VERSION 5.7 ;
BUSBITCHARS "[]" ;
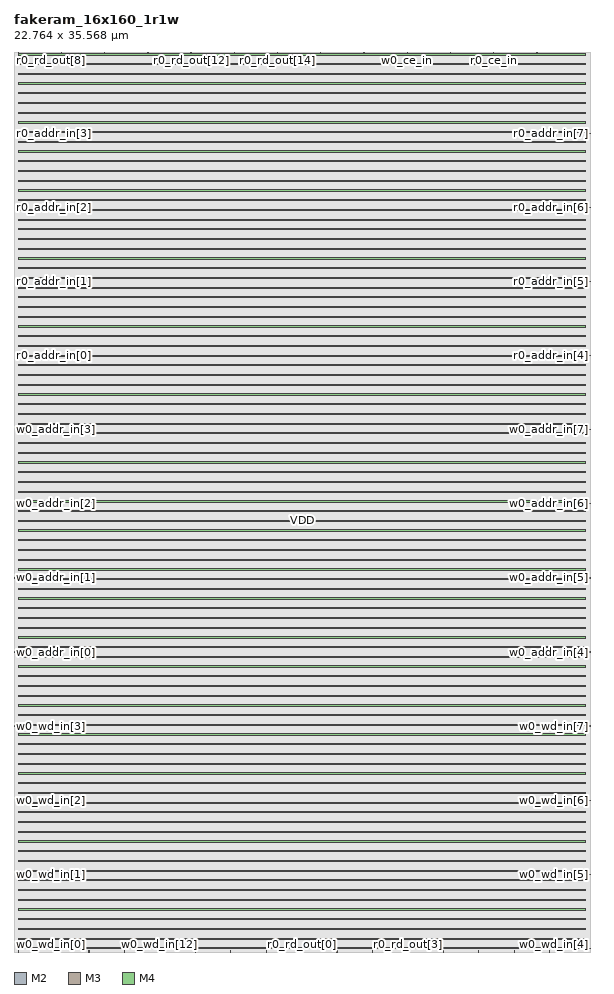
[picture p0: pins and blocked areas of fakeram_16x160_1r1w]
MACRO fakeram_16x160_1r1w
  FOREIGN fakeram_16x160_1r1w 0 0 ;
  SYMMETRY X Y R90 ;
  SIZE 22.764 BY 35.568 ;
  CLASS BLOCK ;
  PIN w0_wd_in[0]
    DIRECTION INPUT ;
    USE SIGNAL ;
    SHAPE ABUTMENT ;
    PORT
      LAYER M2 ;
      RECT 0.000 0.138 0.036 0.150 ;
    END
  END w0_wd_in[0]
  PIN w0_wd_in[1]
    DIRECTION INPUT ;
    USE SIGNAL ;
    SHAPE ABUTMENT ;
    PORT
      LAYER M2 ;
      RECT 0.000 3.066 0.036 3.078 ;
    END
  END w0_wd_in[1]
  PIN w0_wd_in[2]
    DIRECTION INPUT ;
    USE SIGNAL ;
    SHAPE ABUTMENT ;
    PORT
      LAYER M2 ;
      RECT 0.000 5.994 0.036 6.006 ;
    END
  END w0_wd_in[2]
  PIN w0_wd_in[3]
    DIRECTION INPUT ;
    USE SIGNAL ;
    SHAPE ABUTMENT ;
    PORT
      LAYER M2 ;
      RECT 0.000 8.922 0.036 8.934 ;
    END
  END w0_wd_in[3]
  PIN w0_wd_in[4]
    DIRECTION INPUT ;
    USE SIGNAL ;
    SHAPE ABUTMENT ;
    PORT
      LAYER M2 ;
      RECT 22.728 0.138 22.764 0.150 ;
    END
  END w0_wd_in[4]
  PIN w0_wd_in[5]
    DIRECTION INPUT ;
    USE SIGNAL ;
    SHAPE ABUTMENT ;
    PORT
      LAYER M2 ;
      RECT 22.728 3.066 22.764 3.078 ;
    END
  END w0_wd_in[5]
  PIN w0_wd_in[6]
    DIRECTION INPUT ;
    USE SIGNAL ;
    SHAPE ABUTMENT ;
    PORT
      LAYER M2 ;
      RECT 22.728 5.994 22.764 6.006 ;
    END
  END w0_wd_in[6]
  PIN w0_wd_in[7]
    DIRECTION INPUT ;
    USE SIGNAL ;
    SHAPE ABUTMENT ;
    PORT
      LAYER M2 ;
      RECT 22.728 8.922 22.764 8.934 ;
    END
  END w0_wd_in[7]
  PIN w0_wd_in[8]
    DIRECTION INPUT ;
    USE SIGNAL ;
    SHAPE ABUTMENT ;
    PORT
      LAYER M3 ;
      RECT 0.161 0.000 0.175 0.042 ;
    END
  END w0_wd_in[8]
  PIN w0_wd_in[9]
    DIRECTION INPUT ;
    USE SIGNAL ;
    SHAPE ABUTMENT ;
    PORT
      LAYER M3 ;
      RECT 1.561 0.000 1.575 0.042 ;
    END
  END w0_wd_in[9]
  PIN w0_wd_in[10]
    DIRECTION INPUT ;
    USE SIGNAL ;
    SHAPE ABUTMENT ;
    PORT
      LAYER M3 ;
      RECT 2.961 0.000 2.975 0.042 ;
    END
  END w0_wd_in[10]
  PIN w0_wd_in[11]
    DIRECTION INPUT ;
    USE SIGNAL ;
    SHAPE ABUTMENT ;
    PORT
      LAYER M3 ;
      RECT 4.361 0.000 4.375 0.042 ;
    END
  END w0_wd_in[11]
  PIN w0_wd_in[12]
    DIRECTION INPUT ;
    USE SIGNAL ;
    SHAPE ABUTMENT ;
    PORT
      LAYER M3 ;
      RECT 5.761 0.000 5.775 0.042 ;
    END
  END w0_wd_in[12]
  PIN w0_wd_in[13]
    DIRECTION INPUT ;
    USE SIGNAL ;
    SHAPE ABUTMENT ;
    PORT
      LAYER M3 ;
      RECT 7.161 0.000 7.175 0.042 ;
    END
  END w0_wd_in[13]
  PIN w0_wd_in[14]
    DIRECTION INPUT ;
    USE SIGNAL ;
    SHAPE ABUTMENT ;
    PORT
      LAYER M3 ;
      RECT 8.561 0.000 8.575 0.042 ;
    END
  END w0_wd_in[14]
  PIN w0_wd_in[15]
    DIRECTION INPUT ;
    USE SIGNAL ;
    SHAPE ABUTMENT ;
    PORT
      LAYER M3 ;
      RECT 9.961 0.000 9.975 0.042 ;
    END
  END w0_wd_in[15]
  PIN r0_rd_out[0]
    DIRECTION OUTPUT ;
    USE SIGNAL ;
    SHAPE ABUTMENT ;
    PORT
      LAYER M3 ;
      RECT 11.361 0.000 11.375 0.042 ;
    END
  END r0_rd_out[0]
  PIN r0_rd_out[1]
    DIRECTION OUTPUT ;
    USE SIGNAL ;
    SHAPE ABUTMENT ;
    PORT
      LAYER M3 ;
      RECT 12.761 0.000 12.775 0.042 ;
    END
  END r0_rd_out[1]
  PIN r0_rd_out[2]
    DIRECTION OUTPUT ;
    USE SIGNAL ;
    SHAPE ABUTMENT ;
    PORT
      LAYER M3 ;
      RECT 14.161 0.000 14.175 0.042 ;
    END
  END r0_rd_out[2]
  PIN r0_rd_out[3]
    DIRECTION OUTPUT ;
    USE SIGNAL ;
    SHAPE ABUTMENT ;
    PORT
      LAYER M3 ;
      RECT 15.561 0.000 15.575 0.042 ;
    END
  END r0_rd_out[3]
  PIN r0_rd_out[4]
    DIRECTION OUTPUT ;
    USE SIGNAL ;
    SHAPE ABUTMENT ;
    PORT
      LAYER M3 ;
      RECT 16.961 0.000 16.975 0.042 ;
    END
  END r0_rd_out[4]
  PIN r0_rd_out[5]
    DIRECTION OUTPUT ;
    USE SIGNAL ;
    SHAPE ABUTMENT ;
    PORT
      LAYER M3 ;
      RECT 18.361 0.000 18.375 0.042 ;
    END
  END r0_rd_out[5]
  PIN r0_rd_out[6]
    DIRECTION OUTPUT ;
    USE SIGNAL ;
    SHAPE ABUTMENT ;
    PORT
      LAYER M3 ;
      RECT 19.761 0.000 19.775 0.042 ;
    END
  END r0_rd_out[6]
  PIN r0_rd_out[7]
    DIRECTION OUTPUT ;
    USE SIGNAL ;
    SHAPE ABUTMENT ;
    PORT
      LAYER M3 ;
      RECT 21.161 0.000 21.175 0.042 ;
    END
  END r0_rd_out[7]
  PIN r0_rd_out[8]
    DIRECTION OUTPUT ;
    USE SIGNAL ;
    SHAPE ABUTMENT ;
    PORT
      LAYER M3 ;
      RECT 0.161 35.526 0.175 35.568 ;
    END
  END r0_rd_out[8]
  PIN r0_rd_out[9]
    DIRECTION OUTPUT ;
    USE SIGNAL ;
    SHAPE ABUTMENT ;
    PORT
      LAYER M3 ;
      RECT 1.869 35.526 1.883 35.568 ;
    END
  END r0_rd_out[9]
  PIN r0_rd_out[10]
    DIRECTION OUTPUT ;
    USE SIGNAL ;
    SHAPE ABUTMENT ;
    PORT
      LAYER M3 ;
      RECT 3.577 35.526 3.591 35.568 ;
    END
  END r0_rd_out[10]
  PIN r0_rd_out[11]
    DIRECTION OUTPUT ;
    USE SIGNAL ;
    SHAPE ABUTMENT ;
    PORT
      LAYER M3 ;
      RECT 5.285 35.526 5.299 35.568 ;
    END
  END r0_rd_out[11]
  PIN r0_rd_out[12]
    DIRECTION OUTPUT ;
    USE SIGNAL ;
    SHAPE ABUTMENT ;
    PORT
      LAYER M3 ;
      RECT 6.993 35.526 7.007 35.568 ;
    END
  END r0_rd_out[12]
  PIN r0_rd_out[13]
    DIRECTION OUTPUT ;
    USE SIGNAL ;
    SHAPE ABUTMENT ;
    PORT
      LAYER M3 ;
      RECT 8.701 35.526 8.715 35.568 ;
    END
  END r0_rd_out[13]
  PIN r0_rd_out[14]
    DIRECTION OUTPUT ;
    USE SIGNAL ;
    SHAPE ABUTMENT ;
    PORT
      LAYER M3 ;
      RECT 10.409 35.526 10.423 35.568 ;
    END
  END r0_rd_out[14]
  PIN r0_rd_out[15]
    DIRECTION OUTPUT ;
    USE SIGNAL ;
    SHAPE ABUTMENT ;
    PORT
      LAYER M3 ;
      RECT 12.117 35.526 12.131 35.568 ;
    END
  END r0_rd_out[15]
  PIN w0_addr_in[0]
    DIRECTION INPUT ;
    USE SIGNAL ;
    SHAPE ABUTMENT ;
    PORT
      LAYER M2 ;
      RECT 0.000 11.850 0.036 11.862 ;
    END
  END w0_addr_in[0]
  PIN w0_addr_in[1]
    DIRECTION INPUT ;
    USE SIGNAL ;
    SHAPE ABUTMENT ;
    PORT
      LAYER M2 ;
      RECT 0.000 14.778 0.036 14.790 ;
    END
  END w0_addr_in[1]
  PIN w0_addr_in[2]
    DIRECTION INPUT ;
    USE SIGNAL ;
    SHAPE ABUTMENT ;
    PORT
      LAYER M2 ;
      RECT 0.000 17.706 0.036 17.718 ;
    END
  END w0_addr_in[2]
  PIN w0_addr_in[3]
    DIRECTION INPUT ;
    USE SIGNAL ;
    SHAPE ABUTMENT ;
    PORT
      LAYER M2 ;
      RECT 0.000 20.634 0.036 20.646 ;
    END
  END w0_addr_in[3]
  PIN w0_addr_in[4]
    DIRECTION INPUT ;
    USE SIGNAL ;
    SHAPE ABUTMENT ;
    PORT
      LAYER M2 ;
      RECT 22.728 11.850 22.764 11.862 ;
    END
  END w0_addr_in[4]
  PIN w0_addr_in[5]
    DIRECTION INPUT ;
    USE SIGNAL ;
    SHAPE ABUTMENT ;
    PORT
      LAYER M2 ;
      RECT 22.728 14.778 22.764 14.790 ;
    END
  END w0_addr_in[5]
  PIN w0_addr_in[6]
    DIRECTION INPUT ;
    USE SIGNAL ;
    SHAPE ABUTMENT ;
    PORT
      LAYER M2 ;
      RECT 22.728 17.706 22.764 17.718 ;
    END
  END w0_addr_in[6]
  PIN w0_addr_in[7]
    DIRECTION INPUT ;
    USE SIGNAL ;
    SHAPE ABUTMENT ;
    PORT
      LAYER M2 ;
      RECT 22.728 20.634 22.764 20.646 ;
    END
  END w0_addr_in[7]
  PIN r0_addr_in[0]
    DIRECTION INPUT ;
    USE SIGNAL ;
    SHAPE ABUTMENT ;
    PORT
      LAYER M2 ;
      RECT 0.000 23.562 0.036 23.574 ;
    END
  END r0_addr_in[0]
  PIN r0_addr_in[1]
    DIRECTION INPUT ;
    USE SIGNAL ;
    SHAPE ABUTMENT ;
    PORT
      LAYER M2 ;
      RECT 0.000 26.490 0.036 26.502 ;
    END
  END r0_addr_in[1]
  PIN r0_addr_in[2]
    DIRECTION INPUT ;
    USE SIGNAL ;
    SHAPE ABUTMENT ;
    PORT
      LAYER M2 ;
      RECT 0.000 29.418 0.036 29.430 ;
    END
  END r0_addr_in[2]
  PIN r0_addr_in[3]
    DIRECTION INPUT ;
    USE SIGNAL ;
    SHAPE ABUTMENT ;
    PORT
      LAYER M2 ;
      RECT 0.000 32.346 0.036 32.358 ;
    END
  END r0_addr_in[3]
  PIN r0_addr_in[4]
    DIRECTION INPUT ;
    USE SIGNAL ;
    SHAPE ABUTMENT ;
    PORT
      LAYER M2 ;
      RECT 22.728 23.562 22.764 23.574 ;
    END
  END r0_addr_in[4]
  PIN r0_addr_in[5]
    DIRECTION INPUT ;
    USE SIGNAL ;
    SHAPE ABUTMENT ;
    PORT
      LAYER M2 ;
      RECT 22.728 26.490 22.764 26.502 ;
    END
  END r0_addr_in[5]
  PIN r0_addr_in[6]
    DIRECTION INPUT ;
    USE SIGNAL ;
    SHAPE ABUTMENT ;
    PORT
      LAYER M2 ;
      RECT 22.728 29.418 22.764 29.430 ;
    END
  END r0_addr_in[6]
  PIN r0_addr_in[7]
    DIRECTION INPUT ;
    USE SIGNAL ;
    SHAPE ABUTMENT ;
    PORT
      LAYER M2 ;
      RECT 22.728 32.346 22.764 32.358 ;
    END
  END r0_addr_in[7]
  PIN w0_we_in
    DIRECTION INPUT ;
    USE SIGNAL ;
    SHAPE ABUTMENT ;
    PORT
      LAYER M3 ;
      RECT 13.825 35.526 13.839 35.568 ;
    END
  END w0_we_in
  PIN w0_ce_in
    DIRECTION INPUT ;
    USE SIGNAL ;
    SHAPE ABUTMENT ;
    PORT
      LAYER M3 ;
      RECT 15.533 35.526 15.547 35.568 ;
    END
  END w0_ce_in
  PIN w0_clk
    DIRECTION INPUT ;
    USE SIGNAL ;
    SHAPE ABUTMENT ;
    PORT
      LAYER M3 ;
      RECT 17.241 35.526 17.255 35.568 ;
    END
  END w0_clk
  PIN r0_ce_in
    DIRECTION INPUT ;
    USE SIGNAL ;
    SHAPE ABUTMENT ;
    PORT
      LAYER M3 ;
      RECT 18.949 35.526 18.963 35.568 ;
    END
  END r0_ce_in
  PIN r0_clk
    DIRECTION INPUT ;
    USE SIGNAL ;
    SHAPE ABUTMENT ;
    PORT
      LAYER M3 ;
      RECT 20.657 35.526 20.671 35.568 ;
    END
  END r0_clk
  PIN VSS
    DIRECTION INOUT ;
    USE GROUND ;
    PORT
      LAYER M4 ;
      RECT 0.168 0.120 22.596 0.168 ;
      RECT 0.168 0.504 22.596 0.552 ;
      RECT 0.168 0.888 22.596 0.936 ;
      RECT 0.168 1.272 22.596 1.320 ;
      RECT 0.168 1.656 22.596 1.704 ;
      RECT 0.168 2.040 22.596 2.088 ;
      RECT 0.168 2.424 22.596 2.472 ;
      RECT 0.168 2.808 22.596 2.856 ;
      RECT 0.168 3.192 22.596 3.240 ;
      RECT 0.168 3.576 22.596 3.624 ;
      RECT 0.168 3.960 22.596 4.008 ;
      RECT 0.168 4.344 22.596 4.392 ;
      RECT 0.168 4.728 22.596 4.776 ;
      RECT 0.168 5.112 22.596 5.160 ;
      RECT 0.168 5.496 22.596 5.544 ;
      RECT 0.168 5.880 22.596 5.928 ;
      RECT 0.168 6.264 22.596 6.312 ;
      RECT 0.168 6.648 22.596 6.696 ;
      RECT 0.168 7.032 22.596 7.080 ;
      RECT 0.168 7.416 22.596 7.464 ;
      RECT 0.168 7.800 22.596 7.848 ;
      RECT 0.168 8.184 22.596 8.232 ;
      RECT 0.168 8.568 22.596 8.616 ;
      RECT 0.168 8.952 22.596 9.000 ;
      RECT 0.168 9.336 22.596 9.384 ;
      RECT 0.168 9.720 22.596 9.768 ;
      RECT 0.168 10.104 22.596 10.152 ;
      RECT 0.168 10.488 22.596 10.536 ;
      RECT 0.168 10.872 22.596 10.920 ;
      RECT 0.168 11.256 22.596 11.304 ;
      RECT 0.168 11.640 22.596 11.688 ;
      RECT 0.168 12.024 22.596 12.072 ;
      RECT 0.168 12.408 22.596 12.456 ;
      RECT 0.168 12.792 22.596 12.840 ;
      RECT 0.168 13.176 22.596 13.224 ;
      RECT 0.168 13.560 22.596 13.608 ;
      RECT 0.168 13.944 22.596 13.992 ;
      RECT 0.168 14.328 22.596 14.376 ;
      RECT 0.168 14.712 22.596 14.760 ;
      RECT 0.168 15.096 22.596 15.144 ;
      RECT 0.168 15.480 22.596 15.528 ;
      RECT 0.168 15.864 22.596 15.912 ;
      RECT 0.168 16.248 22.596 16.296 ;
      RECT 0.168 16.632 22.596 16.680 ;
      RECT 0.168 17.016 22.596 17.064 ;
      RECT 0.168 17.400 22.596 17.448 ;
      RECT 0.168 17.784 22.596 17.832 ;
      RECT 0.168 18.168 22.596 18.216 ;
      RECT 0.168 18.552 22.596 18.600 ;
      RECT 0.168 18.936 22.596 18.984 ;
      RECT 0.168 19.320 22.596 19.368 ;
      RECT 0.168 19.704 22.596 19.752 ;
      RECT 0.168 20.088 22.596 20.136 ;
      RECT 0.168 20.472 22.596 20.520 ;
      RECT 0.168 20.856 22.596 20.904 ;
      RECT 0.168 21.240 22.596 21.288 ;
      RECT 0.168 21.624 22.596 21.672 ;
      RECT 0.168 22.008 22.596 22.056 ;
      RECT 0.168 22.392 22.596 22.440 ;
      RECT 0.168 22.776 22.596 22.824 ;
      RECT 0.168 23.160 22.596 23.208 ;
      RECT 0.168 23.544 22.596 23.592 ;
      RECT 0.168 23.928 22.596 23.976 ;
      RECT 0.168 24.312 22.596 24.360 ;
      RECT 0.168 24.696 22.596 24.744 ;
      RECT 0.168 25.080 22.596 25.128 ;
      RECT 0.168 25.464 22.596 25.512 ;
      RECT 0.168 25.848 22.596 25.896 ;
      RECT 0.168 26.232 22.596 26.280 ;
      RECT 0.168 26.616 22.596 26.664 ;
      RECT 0.168 27.000 22.596 27.048 ;
      RECT 0.168 27.384 22.596 27.432 ;
      RECT 0.168 27.768 22.596 27.816 ;
      RECT 0.168 28.152 22.596 28.200 ;
      RECT 0.168 28.536 22.596 28.584 ;
      RECT 0.168 28.920 22.596 28.968 ;
      RECT 0.168 29.304 22.596 29.352 ;
      RECT 0.168 29.688 22.596 29.736 ;
      RECT 0.168 30.072 22.596 30.120 ;
      RECT 0.168 30.456 22.596 30.504 ;
      RECT 0.168 30.840 22.596 30.888 ;
      RECT 0.168 31.224 22.596 31.272 ;
      RECT 0.168 31.608 22.596 31.656 ;
      RECT 0.168 31.992 22.596 32.040 ;
      RECT 0.168 32.376 22.596 32.424 ;
      RECT 0.168 32.760 22.596 32.808 ;
      RECT 0.168 33.144 22.596 33.192 ;
      RECT 0.168 33.528 22.596 33.576 ;
      RECT 0.168 33.912 22.596 33.960 ;
      RECT 0.168 34.296 22.596 34.344 ;
      RECT 0.168 34.680 22.596 34.728 ;
      RECT 0.168 35.064 22.596 35.112 ;
      RECT 0.168 35.448 22.596 35.496 ;
    END
  END VSS
  PIN VDD
    DIRECTION INOUT ;
    USE POWER ;
    PORT
      LAYER M4 ;
      RECT 0.168 0.120 22.596 0.168 ;
      RECT 0.168 0.504 22.596 0.552 ;
      RECT 0.168 0.888 22.596 0.936 ;
      RECT 0.168 1.272 22.596 1.320 ;
      RECT 0.168 1.656 22.596 1.704 ;
      RECT 0.168 2.040 22.596 2.088 ;
      RECT 0.168 2.424 22.596 2.472 ;
      RECT 0.168 2.808 22.596 2.856 ;
      RECT 0.168 3.192 22.596 3.240 ;
      RECT 0.168 3.576 22.596 3.624 ;
      RECT 0.168 3.960 22.596 4.008 ;
      RECT 0.168 4.344 22.596 4.392 ;
      RECT 0.168 4.728 22.596 4.776 ;
      RECT 0.168 5.112 22.596 5.160 ;
      RECT 0.168 5.496 22.596 5.544 ;
      RECT 0.168 5.880 22.596 5.928 ;
      RECT 0.168 6.264 22.596 6.312 ;
      RECT 0.168 6.648 22.596 6.696 ;
      RECT 0.168 7.032 22.596 7.080 ;
      RECT 0.168 7.416 22.596 7.464 ;
      RECT 0.168 7.800 22.596 7.848 ;
      RECT 0.168 8.184 22.596 8.232 ;
      RECT 0.168 8.568 22.596 8.616 ;
      RECT 0.168 8.952 22.596 9.000 ;
      RECT 0.168 9.336 22.596 9.384 ;
      RECT 0.168 9.720 22.596 9.768 ;
      RECT 0.168 10.104 22.596 10.152 ;
      RECT 0.168 10.488 22.596 10.536 ;
      RECT 0.168 10.872 22.596 10.920 ;
      RECT 0.168 11.256 22.596 11.304 ;
      RECT 0.168 11.640 22.596 11.688 ;
      RECT 0.168 12.024 22.596 12.072 ;
      RECT 0.168 12.408 22.596 12.456 ;
      RECT 0.168 12.792 22.596 12.840 ;
      RECT 0.168 13.176 22.596 13.224 ;
      RECT 0.168 13.560 22.596 13.608 ;
      RECT 0.168 13.944 22.596 13.992 ;
      RECT 0.168 14.328 22.596 14.376 ;
      RECT 0.168 14.712 22.596 14.760 ;
      RECT 0.168 15.096 22.596 15.144 ;
      RECT 0.168 15.480 22.596 15.528 ;
      RECT 0.168 15.864 22.596 15.912 ;
      RECT 0.168 16.248 22.596 16.296 ;
      RECT 0.168 16.632 22.596 16.680 ;
      RECT 0.168 17.016 22.596 17.064 ;
      RECT 0.168 17.400 22.596 17.448 ;
      RECT 0.168 17.784 22.596 17.832 ;
      RECT 0.168 18.168 22.596 18.216 ;
      RECT 0.168 18.552 22.596 18.600 ;
      RECT 0.168 18.936 22.596 18.984 ;
      RECT 0.168 19.320 22.596 19.368 ;
      RECT 0.168 19.704 22.596 19.752 ;
      RECT 0.168 20.088 22.596 20.136 ;
      RECT 0.168 20.472 22.596 20.520 ;
      RECT 0.168 20.856 22.596 20.904 ;
      RECT 0.168 21.240 22.596 21.288 ;
      RECT 0.168 21.624 22.596 21.672 ;
      RECT 0.168 22.008 22.596 22.056 ;
      RECT 0.168 22.392 22.596 22.440 ;
      RECT 0.168 22.776 22.596 22.824 ;
      RECT 0.168 23.160 22.596 23.208 ;
      RECT 0.168 23.544 22.596 23.592 ;
      RECT 0.168 23.928 22.596 23.976 ;
      RECT 0.168 24.312 22.596 24.360 ;
      RECT 0.168 24.696 22.596 24.744 ;
      RECT 0.168 25.080 22.596 25.128 ;
      RECT 0.168 25.464 22.596 25.512 ;
      RECT 0.168 25.848 22.596 25.896 ;
      RECT 0.168 26.232 22.596 26.280 ;
      RECT 0.168 26.616 22.596 26.664 ;
      RECT 0.168 27.000 22.596 27.048 ;
      RECT 0.168 27.384 22.596 27.432 ;
      RECT 0.168 27.768 22.596 27.816 ;
      RECT 0.168 28.152 22.596 28.200 ;
      RECT 0.168 28.536 22.596 28.584 ;
      RECT 0.168 28.920 22.596 28.968 ;
      RECT 0.168 29.304 22.596 29.352 ;
      RECT 0.168 29.688 22.596 29.736 ;
      RECT 0.168 30.072 22.596 30.120 ;
      RECT 0.168 30.456 22.596 30.504 ;
      RECT 0.168 30.840 22.596 30.888 ;
      RECT 0.168 31.224 22.596 31.272 ;
      RECT 0.168 31.608 22.596 31.656 ;
      RECT 0.168 31.992 22.596 32.040 ;
      RECT 0.168 32.376 22.596 32.424 ;
      RECT 0.168 32.760 22.596 32.808 ;
      RECT 0.168 33.144 22.596 33.192 ;
      RECT 0.168 33.528 22.596 33.576 ;
      RECT 0.168 33.912 22.596 33.960 ;
      RECT 0.168 34.296 22.596 34.344 ;
      RECT 0.168 34.680 22.596 34.728 ;
      RECT 0.168 35.064 22.596 35.112 ;
      RECT 0.168 35.448 22.596 35.496 ;
    END
  END VDD
  OBS
    LAYER M1 ;
    RECT 0 0 22.764 35.568 ;
    LAYER M2 ;
    RECT 0 0 22.764 35.568 ;
    LAYER M3 ;
    RECT 0 0 22.764 35.568 ;
    LAYER M4 ;
    RECT 0 0 22.764 35.568 ;
  END
END fakeram_16x160_1r1w

END LIBRARY
